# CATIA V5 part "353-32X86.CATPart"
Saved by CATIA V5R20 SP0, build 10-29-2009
Part number: 353-32X86
Definition: NONE
Nomenclature: 353-32X86
Source: Unknown
Description: 353-32X86
Bounding box of the stored display mesh (mm): x -7 to 79, y -22.5 to 22.5, z -22.5 to 22.5
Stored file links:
  C:\Users\Utente\Desktop\IO LAVORO\3D X SITO CF\X SITO\PLASTICA\353\353-32X86.CATPart

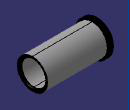
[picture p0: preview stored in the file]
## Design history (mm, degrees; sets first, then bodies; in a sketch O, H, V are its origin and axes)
Body1 "353-32X86" (main body)
  Solid1: solid without history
